VERSION 5.8 ;
BUSBITCHARS "[]" ;
DIVIDERCHAR "/" ;
UNITS
    DATABASE MICRONS 1000 ;
END UNITS

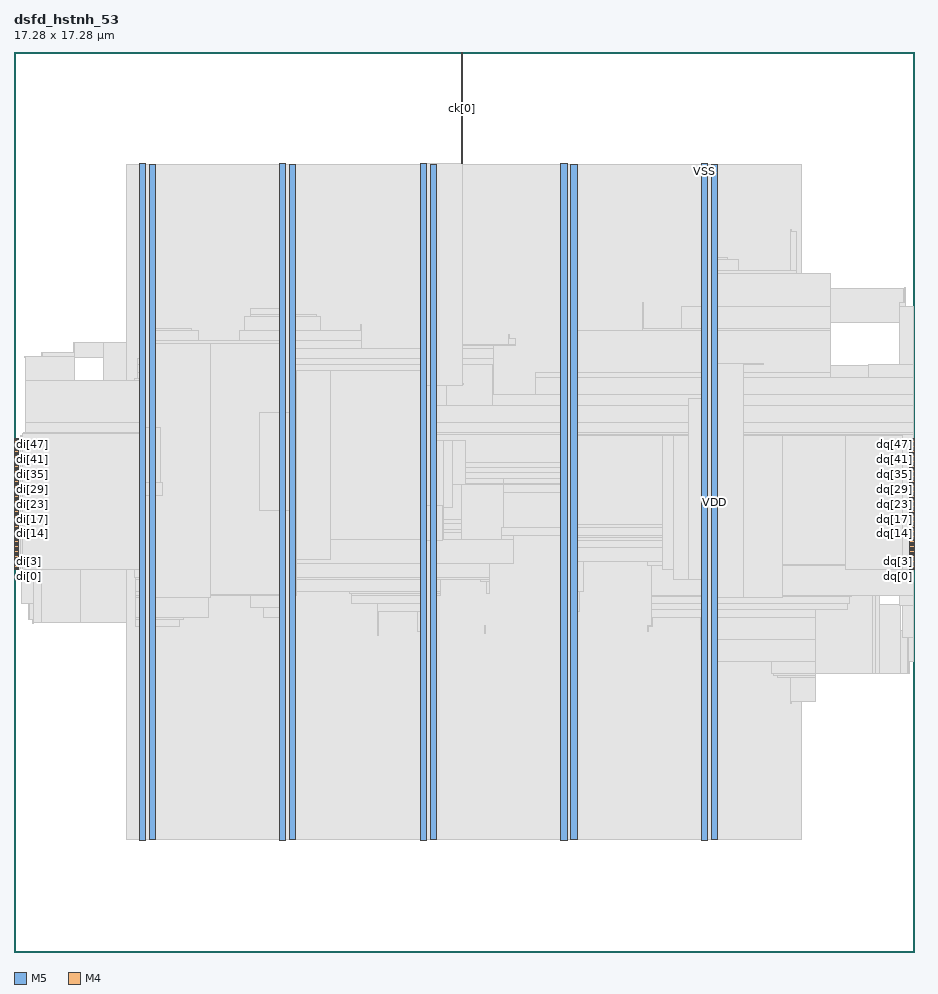
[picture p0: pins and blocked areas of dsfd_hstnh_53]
MACRO dsfd_hstnh_53
  FOREIGN dsfd_hstnh_53 0 0 ;
  CLASS BLOCK ;
  SIZE 17.28 BY 17.28 ;
  PIN ck[0]
    DIRECTION INPUT ;
    USE SIGNAL ;
    PORT
      LAYER M5 ;
        RECT  8.592 17.196 8.616 17.28 ;
    END
    PORT
      LAYER M5 ;
        RECT  8.592 15.143 8.616 17.232 ;
    END
  END ck[0]
  PIN di[0]
    DIRECTION INPUT ;
    USE SIGNAL ;
    PORT
      LAYER M4 ;
        RECT  0 7.344 0.084 7.368 ;
    END
  END di[0]
  PIN di[10]
    DIRECTION INPUT ;
    USE SIGNAL ;
    PORT
      LAYER M4 ;
        RECT  0 7.824 0.084 7.848 ;
    END
  END di[10]
  PIN di[11]
    DIRECTION INPUT ;
    USE SIGNAL ;
    PORT
      LAYER M4 ;
        RECT  0 7.872 0.084 7.896 ;
    END
  END di[11]
  PIN di[12]
    DIRECTION INPUT ;
    USE SIGNAL ;
    PORT
      LAYER M4 ;
        RECT  0 7.92 0.084 7.944 ;
    END
  END di[12]
  PIN di[13]
    DIRECTION INPUT ;
    USE SIGNAL ;
    PORT
      LAYER M4 ;
        RECT  0 7.968 0.084 7.992 ;
    END
  END di[13]
  PIN di[14]
    DIRECTION INPUT ;
    USE SIGNAL ;
    PORT
      LAYER M4 ;
        RECT  0 8.016 0.084 8.04 ;
    END
  END di[14]
  PIN di[15]
    DIRECTION INPUT ;
    USE SIGNAL ;
    PORT
      LAYER M4 ;
        RECT  0 8.064 0.084 8.088 ;
    END
  END di[15]
  PIN di[16]
    DIRECTION INPUT ;
    USE SIGNAL ;
    PORT
      LAYER M4 ;
        RECT  0 8.112 0.084 8.136 ;
    END
  END di[16]
  PIN di[17]
    DIRECTION INPUT ;
    USE SIGNAL ;
    PORT
      LAYER M4 ;
        RECT  0 8.16 0.084 8.184 ;
    END
  END di[17]
  PIN di[18]
    DIRECTION INPUT ;
    USE SIGNAL ;
    PORT
      LAYER M4 ;
        RECT  0 8.208 0.084 8.232 ;
    END
  END di[18]
  PIN di[19]
    DIRECTION INPUT ;
    USE SIGNAL ;
    PORT
      LAYER M4 ;
        RECT  0 8.256 0.084 8.28 ;
    END
  END di[19]
  PIN di[1]
    DIRECTION INPUT ;
    USE SIGNAL ;
    PORT
      LAYER M4 ;
        RECT  0 7.392 0.084 7.416 ;
    END
  END di[1]
  PIN di[20]
    DIRECTION INPUT ;
    USE SIGNAL ;
    PORT
      LAYER M4 ;
        RECT  0 8.304 0.084 8.328 ;
    END
  END di[20]
  PIN di[21]
    DIRECTION INPUT ;
    USE SIGNAL ;
    PORT
      LAYER M4 ;
        RECT  0 8.352 0.084 8.376 ;
    END
  END di[21]
  PIN di[22]
    DIRECTION INPUT ;
    USE SIGNAL ;
    PORT
      LAYER M4 ;
        RECT  0 8.4 0.084 8.424 ;
    END
  END di[22]
  PIN di[23]
    DIRECTION INPUT ;
    USE SIGNAL ;
    PORT
      LAYER M4 ;
        RECT  0 8.448 0.084 8.472 ;
    END
  END di[23]
  PIN di[24]
    DIRECTION INPUT ;
    USE SIGNAL ;
    PORT
      LAYER M4 ;
        RECT  0 8.496 0.084 8.52 ;
    END
  END di[24]
  PIN di[25]
    DIRECTION INPUT ;
    USE SIGNAL ;
    PORT
      LAYER M4 ;
        RECT  0 8.544 0.084 8.568 ;
    END
  END di[25]
  PIN di[26]
    DIRECTION INPUT ;
    USE SIGNAL ;
    PORT
      LAYER M4 ;
        RECT  0 8.592 0.084 8.616 ;
    END
  END di[26]
  PIN di[27]
    DIRECTION INPUT ;
    USE SIGNAL ;
    PORT
      LAYER M4 ;
        RECT  0 8.64 0.084 8.664 ;
    END
  END di[27]
  PIN di[28]
    DIRECTION INPUT ;
    USE SIGNAL ;
    PORT
      LAYER M4 ;
        RECT  0 8.688 0.084 8.712 ;
    END
  END di[28]
  PIN di[29]
    DIRECTION INPUT ;
    USE SIGNAL ;
    PORT
      LAYER M4 ;
        RECT  0 8.736 0.084 8.76 ;
    END
  END di[29]
  PIN di[2]
    DIRECTION INPUT ;
    USE SIGNAL ;
    PORT
      LAYER M4 ;
        RECT  0 7.44 0.084 7.464 ;
    END
  END di[2]
  PIN di[30]
    DIRECTION INPUT ;
    USE SIGNAL ;
    PORT
      LAYER M4 ;
        RECT  0 8.784 0.084 8.808 ;
    END
  END di[30]
  PIN di[31]
    DIRECTION INPUT ;
    USE SIGNAL ;
    PORT
      LAYER M4 ;
        RECT  0 8.832 0.084 8.856 ;
    END
  END di[31]
  PIN di[32]
    DIRECTION INPUT ;
    USE SIGNAL ;
    PORT
      LAYER M4 ;
        RECT  0 8.88 0.084 8.904 ;
    END
  END di[32]
  PIN di[33]
    DIRECTION INPUT ;
    USE SIGNAL ;
    PORT
      LAYER M4 ;
        RECT  0 8.928 0.084 8.952 ;
    END
  END di[33]
  PIN di[34]
    DIRECTION INPUT ;
    USE SIGNAL ;
    PORT
      LAYER M4 ;
        RECT  0 8.976 0.084 9 ;
    END
  END di[34]
  PIN di[35]
    DIRECTION INPUT ;
    USE SIGNAL ;
    PORT
      LAYER M4 ;
        RECT  0 9.024 0.084 9.048 ;
    END
  END di[35]
  PIN di[36]
    DIRECTION INPUT ;
    USE SIGNAL ;
    PORT
      LAYER M4 ;
        RECT  0 9.072 0.084 9.096 ;
    END
  END di[36]
  PIN di[37]
    DIRECTION INPUT ;
    USE SIGNAL ;
    PORT
      LAYER M4 ;
        RECT  0 9.12 0.084 9.144 ;
    END
  END di[37]
  PIN di[38]
    DIRECTION INPUT ;
    USE SIGNAL ;
    PORT
      LAYER M4 ;
        RECT  0 9.168 0.084 9.192 ;
    END
  END di[38]
  PIN di[39]
    DIRECTION INPUT ;
    USE SIGNAL ;
    PORT
      LAYER M4 ;
        RECT  0 9.216 0.084 9.24 ;
    END
  END di[39]
  PIN di[3]
    DIRECTION INPUT ;
    USE SIGNAL ;
    PORT
      LAYER M4 ;
        RECT  0 7.488 0.084 7.512 ;
    END
  END di[3]
  PIN di[40]
    DIRECTION INPUT ;
    USE SIGNAL ;
    PORT
      LAYER M4 ;
        RECT  0 9.264 0.084 9.288 ;
    END
  END di[40]
  PIN di[41]
    DIRECTION INPUT ;
    USE SIGNAL ;
    PORT
      LAYER M4 ;
        RECT  0 9.312 0.084 9.336 ;
    END
  END di[41]
  PIN di[42]
    DIRECTION INPUT ;
    USE SIGNAL ;
    PORT
      LAYER M4 ;
        RECT  0 9.36 0.084 9.384 ;
    END
  END di[42]
  PIN di[43]
    DIRECTION INPUT ;
    USE SIGNAL ;
    PORT
      LAYER M4 ;
        RECT  0 9.408 0.084 9.432 ;
    END
  END di[43]
  PIN di[44]
    DIRECTION INPUT ;
    USE SIGNAL ;
    PORT
      LAYER M4 ;
        RECT  0 9.456 0.084 9.48 ;
    END
  END di[44]
  PIN di[45]
    DIRECTION INPUT ;
    USE SIGNAL ;
    PORT
      LAYER M4 ;
        RECT  0 9.504 0.084 9.528 ;
    END
  END di[45]
  PIN di[46]
    DIRECTION INPUT ;
    USE SIGNAL ;
    PORT
      LAYER M4 ;
        RECT  0 9.552 0.084 9.576 ;
    END
  END di[46]
  PIN di[47]
    DIRECTION INPUT ;
    USE SIGNAL ;
    PORT
      LAYER M4 ;
        RECT  0 9.6 0.084 9.624 ;
    END
  END di[47]
  PIN di[48]
    DIRECTION INPUT ;
    USE SIGNAL ;
    PORT
      LAYER M4 ;
        RECT  0 9.648 0.084 9.672 ;
    END
  END di[48]
  PIN di[49]
    DIRECTION INPUT ;
    USE SIGNAL ;
    PORT
      LAYER M4 ;
        RECT  0 9.696 0.084 9.72 ;
    END
  END di[49]
  PIN di[4]
    DIRECTION INPUT ;
    USE SIGNAL ;
    PORT
      LAYER M4 ;
        RECT  0 7.536 0.084 7.56 ;
    END
  END di[4]
  PIN di[50]
    DIRECTION INPUT ;
    USE SIGNAL ;
    PORT
      LAYER M4 ;
        RECT  0 9.744 0.084 9.768 ;
    END
  END di[50]
  PIN di[51]
    DIRECTION INPUT ;
    USE SIGNAL ;
    PORT
      LAYER M4 ;
        RECT  0 9.792 0.084 9.816 ;
    END
  END di[51]
  PIN di[52]
    DIRECTION INPUT ;
    USE SIGNAL ;
    PORT
      LAYER M4 ;
        RECT  0 9.84 0.084 9.864 ;
    END
  END di[52]
  PIN di[5]
    DIRECTION INPUT ;
    USE SIGNAL ;
    PORT
      LAYER M4 ;
        RECT  0 7.584 0.084 7.608 ;
    END
  END di[5]
  PIN di[6]
    DIRECTION INPUT ;
    USE SIGNAL ;
    PORT
      LAYER M4 ;
        RECT  0 7.632 0.084 7.656 ;
    END
  END di[6]
  PIN di[7]
    DIRECTION INPUT ;
    USE SIGNAL ;
    PORT
      LAYER M4 ;
        RECT  0 7.68 0.084 7.704 ;
    END
  END di[7]
  PIN di[8]
    DIRECTION INPUT ;
    USE SIGNAL ;
    PORT
      LAYER M4 ;
        RECT  0 7.728 0.084 7.752 ;
    END
  END di[8]
  PIN di[9]
    DIRECTION INPUT ;
    USE SIGNAL ;
    PORT
      LAYER M4 ;
        RECT  0 7.776 0.084 7.8 ;
    END
  END di[9]
  PIN dq[0]
    DIRECTION OUTPUT ;
    USE SIGNAL ;
    PORT
      LAYER M4 ;
        RECT  17.196 7.344 17.28 7.368 ;
    END
  END dq[0]
  PIN dq[10]
    DIRECTION OUTPUT ;
    USE SIGNAL ;
    PORT
      LAYER M4 ;
        RECT  17.196 7.824 17.28 7.848 ;
    END
  END dq[10]
  PIN dq[11]
    DIRECTION OUTPUT ;
    USE SIGNAL ;
    PORT
      LAYER M4 ;
        RECT  17.196 7.872 17.28 7.896 ;
    END
  END dq[11]
  PIN dq[12]
    DIRECTION OUTPUT ;
    USE SIGNAL ;
    PORT
      LAYER M4 ;
        RECT  17.196 7.92 17.28 7.944 ;
    END
  END dq[12]
  PIN dq[13]
    DIRECTION OUTPUT ;
    USE SIGNAL ;
    PORT
      LAYER M4 ;
        RECT  17.196 7.968 17.28 7.992 ;
    END
  END dq[13]
  PIN dq[14]
    DIRECTION OUTPUT ;
    USE SIGNAL ;
    PORT
      LAYER M4 ;
        RECT  17.196 8.016 17.28 8.04 ;
    END
  END dq[14]
  PIN dq[15]
    DIRECTION OUTPUT ;
    USE SIGNAL ;
    PORT
      LAYER M4 ;
        RECT  17.196 8.064 17.28 8.088 ;
    END
  END dq[15]
  PIN dq[16]
    DIRECTION OUTPUT ;
    USE SIGNAL ;
    PORT
      LAYER M4 ;
        RECT  17.196 8.112 17.28 8.136 ;
    END
  END dq[16]
  PIN dq[17]
    DIRECTION OUTPUT ;
    USE SIGNAL ;
    PORT
      LAYER M4 ;
        RECT  17.196 8.16 17.28 8.184 ;
    END
  END dq[17]
  PIN dq[18]
    DIRECTION OUTPUT ;
    USE SIGNAL ;
    PORT
      LAYER M4 ;
        RECT  17.196 8.208 17.28 8.232 ;
    END
  END dq[18]
  PIN dq[19]
    DIRECTION OUTPUT ;
    USE SIGNAL ;
    PORT
      LAYER M4 ;
        RECT  17.196 8.256 17.28 8.28 ;
    END
  END dq[19]
  PIN dq[1]
    DIRECTION OUTPUT ;
    USE SIGNAL ;
    PORT
      LAYER M4 ;
        RECT  17.196 7.392 17.28 7.416 ;
    END
  END dq[1]
  PIN dq[20]
    DIRECTION OUTPUT ;
    USE SIGNAL ;
    PORT
      LAYER M4 ;
        RECT  17.196 8.304 17.28 8.328 ;
    END
  END dq[20]
  PIN dq[21]
    DIRECTION OUTPUT ;
    USE SIGNAL ;
    PORT
      LAYER M4 ;
        RECT  17.196 8.352 17.28 8.376 ;
    END
  END dq[21]
  PIN dq[22]
    DIRECTION OUTPUT ;
    USE SIGNAL ;
    PORT
      LAYER M4 ;
        RECT  17.196 8.4 17.28 8.424 ;
    END
  END dq[22]
  PIN dq[23]
    DIRECTION OUTPUT ;
    USE SIGNAL ;
    PORT
      LAYER M4 ;
        RECT  17.196 8.448 17.28 8.472 ;
    END
  END dq[23]
  PIN dq[24]
    DIRECTION OUTPUT ;
    USE SIGNAL ;
    PORT
      LAYER M4 ;
        RECT  17.196 8.496 17.28 8.52 ;
    END
  END dq[24]
  PIN dq[25]
    DIRECTION OUTPUT ;
    USE SIGNAL ;
    PORT
      LAYER M4 ;
        RECT  17.196 8.544 17.28 8.568 ;
    END
  END dq[25]
  PIN dq[26]
    DIRECTION OUTPUT ;
    USE SIGNAL ;
    PORT
      LAYER M4 ;
        RECT  17.196 8.592 17.28 8.616 ;
    END
  END dq[26]
  PIN dq[27]
    DIRECTION OUTPUT ;
    USE SIGNAL ;
    PORT
      LAYER M4 ;
        RECT  17.196 8.64 17.28 8.664 ;
    END
  END dq[27]
  PIN dq[28]
    DIRECTION OUTPUT ;
    USE SIGNAL ;
    PORT
      LAYER M4 ;
        RECT  17.196 8.688 17.28 8.712 ;
    END
  END dq[28]
  PIN dq[29]
    DIRECTION OUTPUT ;
    USE SIGNAL ;
    PORT
      LAYER M4 ;
        RECT  17.196 8.736 17.28 8.76 ;
    END
  END dq[29]
  PIN dq[2]
    DIRECTION OUTPUT ;
    USE SIGNAL ;
    PORT
      LAYER M4 ;
        RECT  17.196 7.44 17.28 7.464 ;
    END
  END dq[2]
  PIN dq[30]
    DIRECTION OUTPUT ;
    USE SIGNAL ;
    PORT
      LAYER M4 ;
        RECT  17.196 8.784 17.28 8.808 ;
    END
  END dq[30]
  PIN dq[31]
    DIRECTION OUTPUT ;
    USE SIGNAL ;
    PORT
      LAYER M4 ;
        RECT  17.196 8.832 17.28 8.856 ;
    END
  END dq[31]
  PIN dq[32]
    DIRECTION OUTPUT ;
    USE SIGNAL ;
    PORT
      LAYER M4 ;
        RECT  17.196 8.88 17.28 8.904 ;
    END
  END dq[32]
  PIN dq[33]
    DIRECTION OUTPUT ;
    USE SIGNAL ;
    PORT
      LAYER M4 ;
        RECT  17.196 8.928 17.28 8.952 ;
    END
  END dq[33]
  PIN dq[34]
    DIRECTION OUTPUT ;
    USE SIGNAL ;
    PORT
      LAYER M4 ;
        RECT  17.196 8.976 17.28 9 ;
    END
  END dq[34]
  PIN dq[35]
    DIRECTION OUTPUT ;
    USE SIGNAL ;
    PORT
      LAYER M4 ;
        RECT  17.196 9.024 17.28 9.048 ;
    END
  END dq[35]
  PIN dq[36]
    DIRECTION OUTPUT ;
    USE SIGNAL ;
    PORT
      LAYER M4 ;
        RECT  17.196 9.072 17.28 9.096 ;
    END
  END dq[36]
  PIN dq[37]
    DIRECTION OUTPUT ;
    USE SIGNAL ;
    PORT
      LAYER M4 ;
        RECT  17.196 9.12 17.28 9.144 ;
    END
  END dq[37]
  PIN dq[38]
    DIRECTION OUTPUT ;
    USE SIGNAL ;
    PORT
      LAYER M4 ;
        RECT  17.196 9.168 17.28 9.192 ;
    END
  END dq[38]
  PIN dq[39]
    DIRECTION OUTPUT ;
    USE SIGNAL ;
    PORT
      LAYER M4 ;
        RECT  17.196 9.216 17.28 9.24 ;
    END
  END dq[39]
  PIN dq[3]
    DIRECTION OUTPUT ;
    USE SIGNAL ;
    PORT
      LAYER M4 ;
        RECT  17.196 7.488 17.28 7.512 ;
    END
  END dq[3]
  PIN dq[40]
    DIRECTION OUTPUT ;
    USE SIGNAL ;
    PORT
      LAYER M4 ;
        RECT  17.196 9.264 17.28 9.288 ;
    END
  END dq[40]
  PIN dq[41]
    DIRECTION OUTPUT ;
    USE SIGNAL ;
    PORT
      LAYER M4 ;
        RECT  17.196 9.312 17.28 9.336 ;
    END
  END dq[41]
  PIN dq[42]
    DIRECTION OUTPUT ;
    USE SIGNAL ;
    PORT
      LAYER M4 ;
        RECT  17.196 9.36 17.28 9.384 ;
    END
  END dq[42]
  PIN dq[43]
    DIRECTION OUTPUT ;
    USE SIGNAL ;
    PORT
      LAYER M4 ;
        RECT  17.196 9.408 17.28 9.432 ;
    END
  END dq[43]
  PIN dq[44]
    DIRECTION OUTPUT ;
    USE SIGNAL ;
    PORT
      LAYER M4 ;
        RECT  17.196 9.456 17.28 9.48 ;
    END
  END dq[44]
  PIN dq[45]
    DIRECTION OUTPUT ;
    USE SIGNAL ;
    PORT
      LAYER M4 ;
        RECT  17.196 9.504 17.28 9.528 ;
    END
  END dq[45]
  PIN dq[46]
    DIRECTION OUTPUT ;
    USE SIGNAL ;
    PORT
      LAYER M4 ;
        RECT  17.196 9.552 17.28 9.576 ;
    END
  END dq[46]
  PIN dq[47]
    DIRECTION OUTPUT ;
    USE SIGNAL ;
    PORT
      LAYER M4 ;
        RECT  17.196 9.6 17.28 9.624 ;
    END
  END dq[47]
  PIN dq[48]
    DIRECTION OUTPUT ;
    USE SIGNAL ;
    PORT
      LAYER M4 ;
        RECT  17.196 9.648 17.28 9.672 ;
    END
  END dq[48]
  PIN dq[49]
    DIRECTION OUTPUT ;
    USE SIGNAL ;
    PORT
      LAYER M4 ;
        RECT  17.196 9.696 17.28 9.72 ;
    END
  END dq[49]
  PIN dq[4]
    DIRECTION OUTPUT ;
    USE SIGNAL ;
    PORT
      LAYER M4 ;
        RECT  17.196 7.536 17.28 7.56 ;
    END
  END dq[4]
  PIN dq[50]
    DIRECTION OUTPUT ;
    USE SIGNAL ;
    PORT
      LAYER M4 ;
        RECT  17.196 9.744 17.28 9.768 ;
    END
  END dq[50]
  PIN dq[51]
    DIRECTION OUTPUT ;
    USE SIGNAL ;
    PORT
      LAYER M4 ;
        RECT  17.196 9.792 17.28 9.816 ;
    END
  END dq[51]
  PIN dq[52]
    DIRECTION OUTPUT ;
    USE SIGNAL ;
    PORT
      LAYER M4 ;
        RECT  17.196 9.84 17.28 9.864 ;
    END
  END dq[52]
  PIN dq[5]
    DIRECTION OUTPUT ;
    USE SIGNAL ;
    PORT
      LAYER M4 ;
        RECT  17.196 7.584 17.28 7.608 ;
    END
  END dq[5]
  PIN dq[6]
    DIRECTION OUTPUT ;
    USE SIGNAL ;
    PORT
      LAYER M4 ;
        RECT  17.196 7.632 17.28 7.656 ;
    END
  END dq[6]
  PIN dq[7]
    DIRECTION OUTPUT ;
    USE SIGNAL ;
    PORT
      LAYER M4 ;
        RECT  17.196 7.68 17.28 7.704 ;
    END
  END dq[7]
  PIN dq[8]
    DIRECTION OUTPUT ;
    USE SIGNAL ;
    PORT
      LAYER M4 ;
        RECT  17.196 7.728 17.28 7.752 ;
    END
  END dq[8]
  PIN dq[9]
    DIRECTION OUTPUT ;
    USE SIGNAL ;
    PORT
      LAYER M4 ;
        RECT  17.196 7.776 17.28 7.8 ;
    END
  END dq[9]
  PIN VDD
    DIRECTION INOUT ;
    USE POWER ;
    PORT
      LAYER M5 ;
        RECT  13.392 2.151 13.512 15.129 ;
        RECT  10.692 2.151 10.812 15.129 ;
        RECT  7.992 2.151 8.112 15.129 ;
        RECT  5.292 2.151 5.412 15.129 ;
        RECT  2.592 2.151 2.712 15.129 ;
    END
  END VDD
  PIN VSS
    DIRECTION INOUT ;
    USE GROUND ;
    PORT
      LAYER M5 ;
        RECT  13.2 2.137 13.32 15.143 ;
        RECT  10.5 2.137 10.62 15.143 ;
        RECT  7.8 2.137 7.92 15.143 ;
        RECT  5.1 2.137 5.22 15.143 ;
        RECT  2.4 2.137 2.52 15.143 ;
    END
  END VSS
  # OT_OBS_CLOSED layer=M5 d_um=1.536 added=0
  OBS
    LAYER RVTN ;
     RECT  2.16 2.16 15.12 2.295 ;
     RECT  2.16 2.565 15.12 2.835 ;
     RECT  2.16 3.105 15.12 3.375 ;
     RECT  2.16 3.645 15.12 3.915 ;
     RECT  2.16 4.185 15.12 4.455 ;
     RECT  2.16 4.725 15.12 4.995 ;
     RECT  2.16 5.265 15.12 5.535 ;
     RECT  2.16 5.805 15.12 6.075 ;
     RECT  2.16 6.345 15.12 6.615 ;
     RECT  2.16 6.885 15.12 7.155 ;
     RECT  2.16 7.425 15.12 7.695 ;
     RECT  2.16 7.965 15.12 8.235 ;
     RECT  2.16 8.505 15.12 8.775 ;
     RECT  2.16 9.045 15.12 9.315 ;
     RECT  2.16 9.585 15.12 9.855 ;
     RECT  2.16 10.125 15.12 10.395 ;
     RECT  2.16 10.665 15.12 10.935 ;
     RECT  2.16 11.205 15.12 11.475 ;
     RECT  2.16 11.745 15.12 12.015 ;
     RECT  2.16 12.285 15.12 12.555 ;
     RECT  2.16 12.825 15.12 13.095 ;
     RECT  2.16 13.365 15.12 13.635 ;
     RECT  2.16 13.905 15.12 14.175 ;
     RECT  2.16 14.445 15.12 14.715 ;
     RECT  2.16 14.985 15.12 15.12 ;
    LAYER RVTP ;
     RECT  2.16 2.295 15.12 2.565 ;
     RECT  2.16 2.835 15.12 3.105 ;
     RECT  2.16 3.375 15.12 3.645 ;
     RECT  2.16 3.915 15.12 4.185 ;
     RECT  2.16 4.455 15.12 4.725 ;
     RECT  2.16 4.995 15.12 5.265 ;
     RECT  2.16 5.535 15.12 5.805 ;
     RECT  2.16 6.075 15.12 6.345 ;
     RECT  2.16 6.615 15.12 6.885 ;
     RECT  2.16 7.155 15.12 7.425 ;
     RECT  2.16 7.695 15.12 7.965 ;
     RECT  2.16 8.235 15.12 8.505 ;
     RECT  2.16 8.775 15.12 9.045 ;
     RECT  2.16 9.315 15.12 9.585 ;
     RECT  2.16 9.855 15.12 10.125 ;
     RECT  2.16 10.395 15.12 10.665 ;
     RECT  2.16 10.935 15.12 11.205 ;
     RECT  2.16 11.475 15.12 11.745 ;
     RECT  2.16 12.015 15.12 12.285 ;
     RECT  2.16 12.555 15.12 12.825 ;
     RECT  2.16 13.095 15.12 13.365 ;
     RECT  2.16 13.635 15.12 13.905 ;
     RECT  2.16 14.175 15.12 14.445 ;
     RECT  2.16 14.715 15.12 14.985 ;
    LAYER M1 ;
     RECT  2.16 2.151 15.12 15.129 ;
    LAYER M2 ;
     RECT  0.103 9.36 0.139 9.504 ;
     RECT  0.139 6.696 0.175 6.714 ;
     RECT  0.175 6.696 0.283 7.416 ;
     RECT  0.283 6.39 0.355 7.416 ;
     RECT  0.355 6.318 0.535 7.416 ;
     RECT  0.139 8.514 0.535 9.648 ;
     RECT  0.211 11.412 0.535 11.43 ;
     RECT  0.535 11.412 1.147 11.502 ;
     RECT  0.535 6.318 1.283 9.648 ;
     RECT  0.247 10.602 1.723 10.62 ;
     RECT  1.147 11.412 1.723 11.7 ;
     RECT  1.283 6.318 2.16 9.576 ;
     RECT  1.723 10.602 2.16 11.7 ;
     RECT  2.16 2.151 15.12 15.129 ;
     RECT  15.12 4.806 15.143 11.268 ;
     RECT  15.143 4.806 15.395 9.684 ;
     RECT  15.12 12.096 15.683 13.014 ;
     RECT  15.143 10.44 16.403 11.268 ;
     RECT  16.403 11.25 16.439 11.268 ;
     RECT  15.395 5.346 16.475 9.504 ;
     RECT  16.403 10.44 16.511 10.494 ;
     RECT  16.475 5.346 16.547 9.414 ;
     RECT  16.547 5.346 16.619 9 ;
     RECT  16.511 10.44 16.943 10.458 ;
     RECT  16.619 5.346 17.015 6.678 ;
     RECT  15.683 12.096 17.087 12.744 ;
     RECT  17.087 12.366 17.123 12.744 ;
     RECT  17.015 5.346 17.159 6.174 ;
     RECT  17.159 5.346 17.195 5.598 ;
     RECT  16.619 7.938 17.195 9 ;
     RECT  17.195 5.58 17.267 5.598 ;
     RECT  17.195 7.938 17.267 7.956 ;
     RECT  17.195 8.982 17.267 9 ;
     RECT  17.123 12.366 17.267 12.384 ;
    LAYER M3 ;
     RECT  2.415 2.143 2.505 2.413 ;
     RECT  5.115 2.143 5.205 2.413 ;
     RECT  7.815 2.143 7.905 2.413 ;
     RECT  10.515 2.143 10.605 2.413 ;
     RECT  13.215 2.143 13.305 2.413 ;
     RECT  14.904 4.765 14.922 4.801 ;
     RECT  14.904 4.801 15.39 5.269 ;
     RECT  14.652 5.269 15.39 5.305 ;
     RECT  14.58 5.305 15.39 5.341 ;
     RECT  13.215 2.413 13.497 5.575 ;
     RECT  14.544 5.341 15.39 5.575 ;
     RECT  17.172 5.341 17.19 5.575 ;
     RECT  13.215 5.575 15.39 6.007 ;
     RECT  17.172 5.575 17.262 6.043 ;
     RECT  7.815 2.413 8.097 6.151 ;
     RECT  2.415 2.413 2.697 6.241 ;
     RECT  12.168 6.151 12.186 6.241 ;
     RECT  9.036 6.115 9.054 6.269 ;
     RECT  12.168 6.241 12.258 6.269 ;
     RECT  0.36 6.313 0.378 6.385 ;
     RECT  2.34 6.241 3.186 6.385 ;
     RECT  2.34 6.385 3.258 6.421 ;
     RECT  5.115 2.413 5.397 6.421 ;
     RECT  12.24 6.269 12.258 6.421 ;
     RECT  13.176 6.007 15.39 6.421 ;
     RECT  6.984 6.079 7.002 6.547 ;
     RECT  7.74 6.151 8.097 6.547 ;
     RECT  10.515 2.413 10.797 6.547 ;
     RECT  12.24 6.421 15.39 6.583 ;
     RECT  4.788 6.421 5.397 6.619 ;
     RECT  17.064 6.043 17.262 6.655 ;
     RECT  0.288 6.385 0.378 6.691 ;
     RECT  6.984 6.547 8.097 6.691 ;
     RECT  12.24 6.583 16.002 6.691 ;
     RECT  2.34 6.421 3.726 6.811 ;
     RECT  12.24 6.691 16.038 6.817 ;
     RECT  2.34 6.811 3.762 6.853 ;
     RECT  4.536 6.619 5.397 6.853 ;
     RECT  6.48 6.691 8.097 6.853 ;
     RECT  12.24 6.817 16.074 6.853 ;
     RECT  16.992 6.655 17.262 6.853 ;
     RECT  6.48 6.853 8.19 6.889 ;
     RECT  2.34 6.853 5.418 6.925 ;
     RECT  6.444 6.889 8.19 6.925 ;
     RECT  10.515 6.547 10.854 6.925 ;
     RECT  9.072 6.889 9.126 7.123 ;
     RECT  2.34 6.925 8.19 7.159 ;
     RECT  8.964 7.123 9.126 7.159 ;
     RECT  2.34 7.159 9.126 7.195 ;
     RECT  12.24 6.853 17.262 7.429 ;
     RECT  2.304 7.195 9.126 7.465 ;
     RECT  10.515 6.925 10.926 7.501 ;
     RECT  12.168 7.429 17.262 7.501 ;
     RECT  10.515 7.501 17.262 7.757 ;
     RECT  0.144 6.691 0.378 7.771 ;
     RECT  10.515 7.757 15.39 7.901 ;
     RECT  2.304 7.465 9.594 7.925 ;
     RECT  10.515 7.901 15.318 7.949 ;
     RECT  16.524 7.757 17.262 7.961 ;
     RECT  9.36 7.925 9.594 8.005 ;
     RECT  10.515 7.949 15.138 8.005 ;
     RECT  2.304 7.925 8.586 8.059 ;
     RECT  2.232 8.059 8.586 8.107 ;
     RECT  9.36 8.005 15.138 8.159 ;
     RECT  2.16 8.107 8.586 8.231 ;
     RECT  2.232 8.231 8.586 8.303 ;
     RECT  16.524 7.961 17.19 8.587 ;
     RECT  16.488 8.587 17.19 8.77 ;
     RECT  9.396 8.159 15.138 8.827 ;
     RECT  0.144 7.771 0.558 8.971 ;
     RECT  16.452 8.77 17.19 8.977 ;
     RECT  2.304 8.303 8.586 9.085 ;
     RECT  9.396 8.827 15.678 9.085 ;
     RECT  2.304 9.085 15.678 9.211 ;
     RECT  16.452 8.977 17.262 9.211 ;
     RECT  2.268 9.211 15.678 9.307 ;
     RECT  16.416 9.211 17.262 9.307 ;
     RECT  2.268 9.307 17.262 9.403 ;
     RECT  0.108 8.971 0.558 9.533 ;
     RECT  0.144 9.533 0.558 9.595 ;
     RECT  0.144 9.595 1.278 9.653 ;
     RECT  0.18 9.653 1.278 9.931 ;
     RECT  2.232 9.403 17.262 9.931 ;
     RECT  0.18 9.931 17.262 9.965 ;
     RECT  0.216 9.965 17.262 10.157 ;
     RECT  7.812 10.157 17.262 10.499 ;
     RECT  9.18 10.499 17.262 10.697 ;
     RECT  0.216 10.157 7.038 10.967 ;
     RECT  2.304 10.967 7.038 11.003 ;
     RECT  10.008 10.697 17.262 11.039 ;
     RECT  10.008 11.039 15.678 11.129 ;
     RECT  2.376 11.003 7.038 11.131 ;
     RECT  7.812 10.499 8.298 11.131 ;
     RECT  16.416 11.039 17.262 11.273 ;
     RECT  2.376 11.131 8.298 11.281 ;
     RECT  9.18 10.697 9.198 11.281 ;
     RECT  2.376 11.281 9.198 11.399 ;
     RECT  0.216 10.967 1.17 11.435 ;
     RECT  0.54 11.435 1.17 11.507 ;
     RECT  2.415 11.399 9.198 11.579 ;
     RECT  7.815 11.579 9.198 11.641 ;
     RECT  7.815 11.641 9.63 11.669 ;
     RECT  1.152 11.507 1.17 11.705 ;
     RECT  2.415 11.579 6.678 11.741 ;
     RECT  9.504 11.669 9.63 11.777 ;
     RECT  7.815 11.669 8.586 11.849 ;
     RECT  9.504 11.777 9.522 11.849 ;
     RECT  2.415 11.741 3.546 11.939 ;
     RECT  4.32 11.741 6.678 11.939 ;
     RECT  10.515 11.129 15.678 11.939 ;
     RECT  2.415 11.939 3.402 11.975 ;
     RECT  12.06 11.939 15.678 11.975 ;
     RECT  6.66 11.939 6.678 12.047 ;
     RECT  4.428 11.939 5.886 12.209 ;
     RECT  4.536 12.209 5.814 12.245 ;
     RECT  4.536 12.245 5.397 12.353 ;
     RECT  12.816 11.975 15.678 12.389 ;
     RECT  16.992 11.273 17.262 12.389 ;
     RECT  12.06 11.975 12.078 12.479 ;
     RECT  16.992 12.389 17.118 12.479 ;
     RECT  17.1 12.479 17.118 12.749 ;
     RECT  13.215 12.389 15.678 13.019 ;
     RECT  13.215 13.019 15.03 13.091 ;
     RECT  13.215 13.091 13.914 13.289 ;
     RECT  13.215 13.289 13.698 13.325 ;
     RECT  14.904 13.091 15.03 13.829 ;
     RECT  14.904 13.829 14.922 13.865 ;
     RECT  2.415 11.975 2.697 14.867 ;
     RECT  5.115 12.353 5.397 14.867 ;
     RECT  7.815 11.849 8.097 14.867 ;
     RECT  10.515 11.939 10.797 14.867 ;
     RECT  13.215 13.325 13.497 14.867 ;
     RECT  2.415 14.867 2.505 15.137 ;
     RECT  5.115 14.867 5.205 15.137 ;
     RECT  7.815 14.867 7.905 15.137 ;
     RECT  10.515 14.867 10.605 15.137 ;
     RECT  13.215 14.867 13.305 15.137 ;
    LAYER M4 ;
     RECT  0.06 7.344 0.133 9.864 ;
     RECT  0.133 7.344 0.169 9.912 ;
     RECT  0.169 7.344 2.408 9.96 ;
     RECT  2.408 2.148 2.512 15.132 ;
     RECT  2.512 2.418 2.704 14.862 ;
     RECT  2.704 6.816 3.773 11.688 ;
     RECT  3.773 6.864 5.108 11.688 ;
     RECT  5.108 2.148 5.212 15.132 ;
     RECT  5.212 2.418 5.404 14.862 ;
     RECT  5.404 6.864 5.429 11.16 ;
     RECT  5.429 7.536 6.077 11.16 ;
     RECT  6.077 7.92 7.808 11.16 ;
     RECT  7.808 2.148 7.912 15.132 ;
     RECT  7.912 2.418 8.104 14.862 ;
     RECT  8.104 10.896 8.165 11.016 ;
     RECT  8.104 7.92 8.243 9.816 ;
     RECT  8.243 8.544 8.417 9.816 ;
     RECT  8.165 10.896 8.627 10.92 ;
     RECT  8.417 8.976 8.669 9.816 ;
     RECT  8.669 8.976 10.508 9 ;
     RECT  10.508 2.148 10.612 15.132 ;
     RECT  10.612 2.418 10.804 14.862 ;
     RECT  10.804 8.208 12.445 9.912 ;
     RECT  12.445 7.344 12.661 9.912 ;
     RECT  12.661 7.152 12.949 9.912 ;
     RECT  12.949 7.152 13.208 10.632 ;
     RECT  13.208 2.148 13.312 15.132 ;
     RECT  13.312 2.418 13.504 14.862 ;
     RECT  13.504 6.816 13.997 11.304 ;
     RECT  13.997 11.28 14.393 11.304 ;
     RECT  13.997 6.816 14.753 9.912 ;
     RECT  14.753 7.44 15.973 9.912 ;
     RECT  15.973 7.344 17.057 9.912 ;
     RECT  17.057 7.344 17.244 9.864 ;
    LAYER M5 ;
     RECT  2.4 2.137 2.52 2.151 ;
     RECT  5.1 2.137 5.22 2.151 ;
     RECT  7.8 2.137 7.92 2.151 ;
     RECT  10.5 2.137 10.62 2.151 ;
     RECT  13.2 2.137 13.32 2.151 ;
     RECT  7.8 2.151 8.112 7.909 ;
     RECT  5.1 2.151 5.412 8.485 ;
     RECT  7.8 7.909 8.232 8.579 ;
     RECT  2.4 2.151 2.712 8.773 ;
     RECT  0.336 8.821 0.36 8.963 ;
     RECT  2.4 8.773 2.856 9.011 ;
     RECT  0.24 9.349 0.264 9.539 ;
     RECT  0.144 9.781 0.168 9.923 ;
     RECT  2.4 9.011 2.808 10.067 ;
     RECT  4.704 8.485 5.412 10.355 ;
     RECT  7.8 8.579 8.112 10.885 ;
     RECT  2.4 10.067 2.712 15.129 ;
     RECT  5.1 10.355 5.412 15.129 ;
     RECT  10.5 2.151 10.812 15.129 ;
     RECT  13.2 2.151 13.512 15.129 ;
     RECT  2.4 15.129 2.52 15.143 ;
     RECT  5.1 15.129 5.22 15.143 ;
     RECT  7.8 10.885 8.616 15.143 ;
     RECT  10.5 15.129 10.62 15.143 ;
     RECT  13.2 15.129 13.32 15.143 ;
  END
END dsfd_hstnh_53
END LIBRARY
